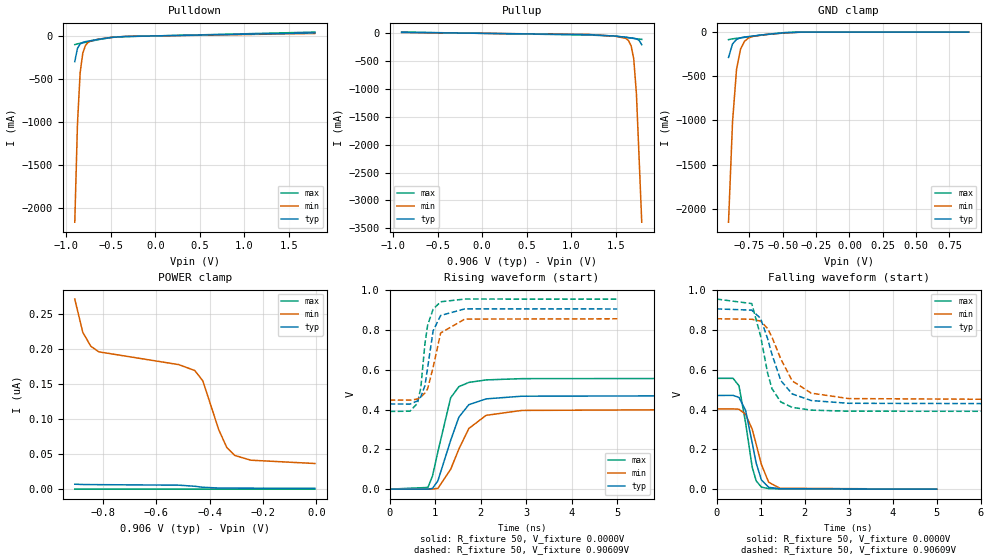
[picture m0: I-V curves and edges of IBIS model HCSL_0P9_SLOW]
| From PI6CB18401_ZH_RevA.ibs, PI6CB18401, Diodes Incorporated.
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[Model]   HCSL_0P9_SLOW
Model_type Output
Vref=0.9000V
Vmeas=900mV
| variable   typ   min   max
C_comp   2.000pF   1.970pF   2.030pF
[Voltage Range]   0.90609V   0.85650V   0.95550V
[POWER Clamp Reference]   0.90609V   0.85650V   0.95550V
[GND Clamp Reference]   0.0000V   0.0000V   0.0000V
[Pullup Reference]   0.90609V   0.85650V   0.95550V
[Pulldown Reference]   0.0000V   0.0000V   0.0000V
[Temperature Range]   25   85   -40
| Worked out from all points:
|   slope of the pulldown table from 0 to 0.136 V, typ, clamps not added: 43.9 ohm
|   slope of the pullup table from 0 to 0.136 V, typ, clamps not added: 46.1 ohm
|   GND clamp passes 1 mA (typ) near -0.37 V on its own axis
|   falling waveform, R_fixture 50, V_fixture 0.0000V: 20-80 % time 259ps typ, 302ps min, 221ps max; typ from 0.471 V to 0 V
|   rising waveform, R_fixture 50, V_fixture 0.0000V: 20-80 % time 409ps typ, 492ps min, 328ps max; typ from 0 V to 0.471 V
|   falling waveform, R_fixture 50, V_fixture 0.90609V: 20-80 % time 432ps typ, 545ps min, 330ps max; typ from 0.906 V to 0.428 V
|   rising waveform, R_fixture 50, V_fixture 0.90609V: 20-80 % time 194ps typ, 227ps min, 172ps max; typ from 0.428 V to 0.906 V
[GND Clamp]
| Voltage   I(typ)   I(min)   I(max)
-906.1mV  -286.6mA   -2.151A    -85.45mA
-876.1mV  -133.8mA   -1.017A    -76.33mA
-846.1mV  -83.21mA   -420.9mA   -70.35mA
-816.1mV  -64.75mA   -192.1mA   -65.15mA
-786.1mV  -56.15mA   -103mA     -59.83mA
-756.1mV  -50.17mA   -66.66mA   -53.95mA
-726.1mV  -44.73mA   -50.08mA   -47.66mA
-636.1mV  -29.01mA   -29.59mA   -28.7mA
-486.1mV  -8.023mA   -10.08mA   -5.373mA
-366.1mV  -792.8uA   -1.762mA   -189.4uA
893.9mV   1.274nA    37.22nA    5.411pA
[POWER Clamp]
| Voltage   I(typ)   I(min)   I(max)
-906.1mV  7.102nA    272nA      64.05pA
-876.1mV  6.695nA    224.4nA    62.62pA
-846.1mV  6.537nA    204.6nA    61.28pA
-816.1mV  6.464nA    196.5nA    59.94pA
-516.1mV  5.725nA    178.2nA    42.48pA
-456.1mV  4.154nA    169.7nA    33.31pA
-426.1mV  2.718nA    154.9nA    31.21pA
-366.1mV  1.642nA    84.73nA    27.91pA
-336.1mV  1.538nA    59.52nA    26.32pA
-306.1mV  1.492nA    48.22nA    24.74pA
-246.1mV  1.442nA    41.44nA    21.59pA
-6.09mV   1.286nA    36.73nA    8.971pA
[Pulldown]
| Voltage   I(typ)   I(min)   I(max)
-906.1mV  -299.2mA   -2.161A    -102.5mA
-876.1mV  -146.3mA   -1.027A    -93.22mA
-846.1mV  -95.54mA   -430.5mA   -87.06mA
-816.1mV  -76.95mA   -201.7mA   -81.68mA
-786.1mV  -68.2mA    -112.5mA   -76.16mA
-756.1mV  -62.06mA   -75.95mA   -70.08mA
-726.1mV  -56.46mA   -59.25mA   -63.56mA
-636.1mV  -40.19mA   -38.34mA   -43.86mA
-486.1mV  -17.93mA   -17.86mA   -18.7mA
-336.1mV  -7.911mA   -7.047mA   -9.887mA
1.794V    33.19mA    26.85mA    42.72mA
[Pullup]
| Voltage   I(typ)   I(min)   I(max)
-906.1mV  16mA       13.17mA    20.24mA
1.194V    -25.61mA   -22.08mA   -32.46mA
1.494V    -51.42mA   -53.83mA   -51.13mA
1.614V    -72.36mA   -92.15mA   -74.09mA
1.644V    -77.85mA   -130mA     -80.63mA
1.674V    -83.5mA    -222.9mA   -87.26mA
1.704V    -90.18mA   -461.5mA   -93.77mA
1.734V    -101.4mA   -1.083A    -99.9mA
1.764V    -128.3mA   -2.227A    -105.5mA
1.794V    -205.8mA   -3.39A     -110.7mA
[Falling Waveform]
R_fixture = 50
V_fixture = 0.0000V
V_fixture_min = 0.0000V
V_fixture_max = 0.0000V
|   Time   V(typ)   V(min)   V(max)
0s        471mV      403.2mV    557.1mV
375ps     471.5mV    403.3mV    557.1mV
510ps     461mV      401.8mV    519.9mV
660ps     396.4mV    376.2mV    334mV
810ps     233.2mV    301.7mV    110.9mV
900ps     131.8mV    226.5mV    42.28mV
1.02ns    46.14mV    123.5mV    10.13mV
1.185ns   9.172mV    34.78mV    3.039mV
1.44ns    2.254mV    4.636mV    1.299mV
5ns       29.76uV    40.46uV    23.68uV
[Rising Waveform]
R_fixture = 50
V_fixture = 0.0000V
V_fixture_min = 0.0000V
V_fixture_max = 0.0000V
|   Time   V(typ)   V(min)   V(max)
0s        11.38uV    11.97uV    11.46uV
840ps     -96.91uV   -131.2uV   8.542mV
940ps     3.465mV    346.4uV    65.09mV
1.06ns    42.22mV    4.059mV    189mV
1.34ns    245.4mV    99.68mV    459.4mV
1.52ns    361.9mV    201.6mV    515.3mV
1.74ns    425mV      305.4mV    536.7mV
2.12ns    453.9mV    371.2mV    549.3mV
2.9ns     467.3mV    395.8mV    555.6mV
10ns      471mV      403.2mV    557.1mV
[Falling Waveform]
R_fixture = 50
V_fixture = 0.90609V
V_fixture_min = 0.85650V
V_fixture_max = 0.95550V
|   Time   V(typ)   V(min)   V(max)
0s        906.1mV    856.5mV    955.5mV
800ps     899.8mV    854mV      932.8mV
1ns       858.7mV    845.1mV    770.8mV
1.16ns    756.8mV    807.7mV    583.9mV
1.26ns    677.3mV    764.1mV    504.9mV
1.46ns    545.7mV    654.5mV    438.4mV
1.72ns    478.7mV    544.2mV    411mV
2.15ns    445.6mV    482.7mV    397.3mV
3ns       431.6mV    455.3mV    391.8mV
10ns      428.3mV    447.6mV    390.8mV
[Rising Waveform]
R_fixture = 50
V_fixture = 0.90609V
V_fixture_min = 0.85650V
V_fixture_max = 0.95550V
|   Time   V(typ)   V(min)   V(max)
0s        428.3mV    447.6mV    390.8mV
445ps     427.6mV    447.6mV    391.9mV
610ps     443.4mV    453mV      431.5mV
685ps     464.1mV    462.9mV    510.2mV
775ps     520.9mV    483.1mV    732mV
835ps     612.2mV    505.6mV    825.2mV
955ps     796.1mV    612.4mV    905mV
1.12ns    873.3mV    785.2mV    942.2mV
1.65ns    906.4mV    855.2mV    955.8mV
5ns       906.1mV    856.5mV    955.5mV
[Ramp]
| variable   typ   min   max
dV/dt_r   0.28313V/408.49p   0.24226V/491.08p   0.33435V/327.79p
dV/dt_f   0.28654V/432.07p   0.24530V/543.44p   0.33850V/329.34p
R_load = 50
